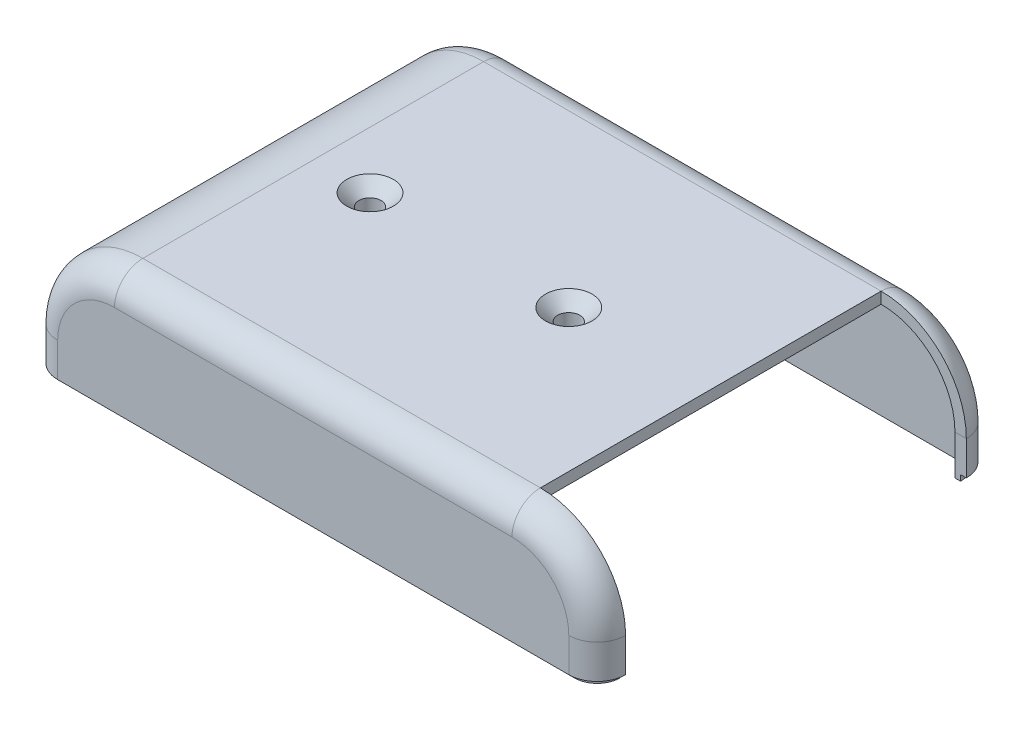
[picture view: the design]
ISO-10303-21;
HEADER;
FILE_DESCRIPTION(('STEP AP214'),'2;1');
FILE_NAME('part.step','',(''),(''),'','','');
FILE_SCHEMA(('AUTOMOTIVE_DESIGN { 1 0 10303 214 1 1 1 1 }'));
ENDSEC;
DATA;
#1=APPLICATION_CONTEXT('core data for automotive mechanical design processes');
#2=APPLICATION_PROTOCOL_DEFINITION('international standard','automotive_design',2000,#1);
#3=PRODUCT_CONTEXT('',#1,'mechanical');
#4=PRODUCT('Part','Part','',(#3));
#5=PRODUCT_RELATED_PRODUCT_CATEGORY('part','',(#4));
#6=PRODUCT_DEFINITION_FORMATION('','',#4);
#7=PRODUCT_DEFINITION_CONTEXT('part definition',#1,'design');
#8=PRODUCT_DEFINITION('design','',#6,#7);
#9=PRODUCT_DEFINITION_SHAPE('','',#8);
#10=(LENGTH_UNIT() NAMED_UNIT(*) SI_UNIT(.MILLI.,.METRE.));
#11=(NAMED_UNIT(*) PLANE_ANGLE_UNIT() SI_UNIT($,.RADIAN.));
#12=(NAMED_UNIT(*) SI_UNIT($,.STERADIAN.) SOLID_ANGLE_UNIT());
#13=UNCERTAINTY_MEASURE_WITH_UNIT(LENGTH_MEASURE(1.E-05),#10,'distance_accuracy_value','');
#14=(GEOMETRIC_REPRESENTATION_CONTEXT(3) GLOBAL_UNCERTAINTY_ASSIGNED_CONTEXT((#13)) GLOBAL_UNIT_ASSIGNED_CONTEXT((#10,
#11,#12)) REPRESENTATION_CONTEXT('',''));
#15=CARTESIAN_POINT('',(0.,0.,0.));
#16=DIRECTION('',(0.,0.,1.));
#17=DIRECTION('',(1.,0.,0.));
#18=AXIS2_PLACEMENT_3D('',#15,#16,#17);
#19=CARTESIAN_POINT('',(-50.,21.,-35.));
#20=DIRECTION('',(0.,0.,1.));
#21=DIRECTION('',(1.,0.,0.));
#22=AXIS2_PLACEMENT_3D('',#19,#20,#21);
#23=PLANE('',#22);
#24=CARTESIAN_POINT('',(35.,6.,-35.));
#25=DIRECTION('',(0.,0.,1.));
#26=DIRECTION('',(1.,0.,0.));
#27=AXIS2_PLACEMENT_3D('',#24,#25,#26);
#28=CIRCLE('',#27,10.);
#29=CARTESIAN_POINT('',(35.,16.,-35.));
#30=VERTEX_POINT('',#29);
#31=CARTESIAN_POINT('',(45.,6.,-35.));
#32=VERTEX_POINT('',#31);
#33=EDGE_CURVE('E472',#30,#32,#28,.F.);
#34=ORIENTED_EDGE('',*,*,#33,.T.);
#35=DIRECTION('',(0.,-1.,0.));
#36=VECTOR('',#35,1.);
#37=CARTESIAN_POINT('',(45.,21.,-35.));
#38=LINE('',#37,#36);
#39=CARTESIAN_POINT('',(45.,0.,-35.));
#40=VERTEX_POINT('',#39);
#41=EDGE_CURVE('E474',#32,#40,#38,.T.);
#42=ORIENTED_EDGE('',*,*,#41,.T.);
#43=DIRECTION('',(-1.,0.,0.));
#44=VECTOR('',#43,1.);
#45=CARTESIAN_POINT('',(-50.,0.,-35.));
#46=LINE('',#45,#44);
#47=CARTESIAN_POINT('',(-45.,0.,-35.));
#48=VERTEX_POINT('',#47);
#49=EDGE_CURVE('E447',#40,#48,#46,.T.);
#50=ORIENTED_EDGE('',*,*,#49,.T.);
#51=DIRECTION('',(0.,-1.,0.));
#52=VECTOR('',#51,1.);
#53=CARTESIAN_POINT('',(-45.,21.,-35.));
#54=LINE('',#53,#52);
#55=CARTESIAN_POINT('',(-45.,6.,-35.));
#56=VERTEX_POINT('',#55);
#57=EDGE_CURVE('E470',#48,#56,#54,.F.);
#58=ORIENTED_EDGE('',*,*,#57,.T.);
#59=CARTESIAN_POINT('',(-35.,6.,-35.));
#60=DIRECTION('',(0.,0.,1.));
#61=DIRECTION('',(1.,0.,0.));
#62=AXIS2_PLACEMENT_3D('',#59,#60,#61);
#63=CIRCLE('',#62,10.);
#64=CARTESIAN_POINT('',(-35.,16.,-35.));
#65=VERTEX_POINT('',#64);
#66=EDGE_CURVE('E468',#56,#65,#63,.F.);
#67=ORIENTED_EDGE('',*,*,#66,.T.);
#68=DIRECTION('',(-1.,0.,0.));
#69=VECTOR('',#68,1.);
#70=CARTESIAN_POINT('',(-50.,16.,-35.));
#71=LINE('',#70,#69);
#72=EDGE_CURVE('E466',#65,#30,#71,.F.);
#73=ORIENTED_EDGE('',*,*,#72,.T.);
#74=EDGE_LOOP('',(#34,#42,#50,#58,#67,#73));
#75=FACE_BOUND('',#74,.T.);
#76=ADVANCED_FACE('F36',(#75),#23,.F.);
#77=CARTESIAN_POINT('',(-50.,21.,35.));
#78=DIRECTION('',(1.,0.,0.));
#79=DIRECTION('',(0.,0.,-1.));
#80=AXIS2_PLACEMENT_3D('',#77,#78,#79);
#81=PLANE('',#80);
#82=DIRECTION('',(0.,0.,1.));
#83=VECTOR('',#82,1.);
#84=CARTESIAN_POINT('',(-50.,6.,35.));
#85=LINE('',#84,#83);
#86=CARTESIAN_POINT('',(-50.,6.,30.));
#87=VERTEX_POINT('',#86);
#88=CARTESIAN_POINT('',(-50.,6.,-30.));
#89=VERTEX_POINT('',#88);
#90=EDGE_CURVE('E463',#87,#89,#85,.F.);
#91=ORIENTED_EDGE('',*,*,#90,.T.);
#92=DIRECTION('',(0.,-1.,0.));
#93=VECTOR('',#92,1.);
#94=CARTESIAN_POINT('',(-50.,21.,-30.));
#95=LINE('',#94,#93);
#96=CARTESIAN_POINT('',(-50.,0.,-30.));
#97=VERTEX_POINT('',#96);
#98=EDGE_CURVE('E497',#89,#97,#95,.T.);
#99=ORIENTED_EDGE('',*,*,#98,.T.);
#100=DIRECTION('',(0.,0.,1.));
#101=VECTOR('',#100,1.);
#102=CARTESIAN_POINT('',(-50.,0.,35.));
#103=LINE('',#102,#101);
#104=CARTESIAN_POINT('',(-50.,0.,30.));
#105=VERTEX_POINT('',#104);
#106=EDGE_CURVE('E450',#97,#105,#103,.T.);
#107=ORIENTED_EDGE('',*,*,#106,.T.);
#108=DIRECTION('',(0.,-1.,0.));
#109=VECTOR('',#108,1.);
#110=CARTESIAN_POINT('',(-50.,21.,30.));
#111=LINE('',#110,#109);
#112=EDGE_CURVE('E495',#105,#87,#111,.F.);
#113=ORIENTED_EDGE('',*,*,#112,.T.);
#114=EDGE_LOOP('',(#91,#99,#107,#113));
#115=FACE_BOUND('',#114,.T.);
#116=ADVANCED_FACE('F582',(#115),#81,.F.);
#117=CARTESIAN_POINT('',(-50.,21.,35.));
#118=DIRECTION('',(0.,0.,-1.));
#119=DIRECTION('',(-1.,0.,0.));
#120=AXIS2_PLACEMENT_3D('',#117,#118,#119);
#121=PLANE('',#120);
#122=CARTESIAN_POINT('',(-35.,6.,35.));
#123=DIRECTION('',(0.,0.,-1.));
#124=DIRECTION('',(-1.,0.,0.));
#125=AXIS2_PLACEMENT_3D('',#122,#123,#124);
#126=CIRCLE('',#125,10.);
#127=CARTESIAN_POINT('',(-35.,16.,35.));
#128=VERTEX_POINT('',#127);
#129=CARTESIAN_POINT('',(-45.,6.,35.));
#130=VERTEX_POINT('',#129);
#131=EDGE_CURVE('E509',#128,#130,#126,.F.);
#132=ORIENTED_EDGE('',*,*,#131,.T.);
#133=DIRECTION('',(0.,-1.,0.));
#134=VECTOR('',#133,1.);
#135=CARTESIAN_POINT('',(-45.,21.,35.));
#136=LINE('',#135,#134);
#137=CARTESIAN_POINT('',(-45.,0.,35.));
#138=VERTEX_POINT('',#137);
#139=EDGE_CURVE('E511',#130,#138,#136,.T.);
#140=ORIENTED_EDGE('',*,*,#139,.T.);
#141=DIRECTION('',(1.,0.,0.));
#142=VECTOR('',#141,1.);
#143=CARTESIAN_POINT('',(-50.,0.,35.));
#144=LINE('',#143,#142);
#145=CARTESIAN_POINT('',(45.,0.,35.));
#146=VERTEX_POINT('',#145);
#147=EDGE_CURVE('E454',#138,#146,#144,.T.);
#148=ORIENTED_EDGE('',*,*,#147,.T.);
#149=DIRECTION('',(0.,-1.,0.));
#150=VECTOR('',#149,1.);
#151=CARTESIAN_POINT('',(45.,21.,35.));
#152=LINE('',#151,#150);
#153=CARTESIAN_POINT('',(45.,6.,35.));
#154=VERTEX_POINT('',#153);
#155=EDGE_CURVE('E507',#146,#154,#152,.F.);
#156=ORIENTED_EDGE('',*,*,#155,.T.);
#157=CARTESIAN_POINT('',(35.,6.,35.));
#158=DIRECTION('',(0.,0.,-1.));
#159=DIRECTION('',(-1.,0.,0.));
#160=AXIS2_PLACEMENT_3D('',#157,#158,#159);
#161=CIRCLE('',#160,10.);
#162=CARTESIAN_POINT('',(35.,16.,35.));
#163=VERTEX_POINT('',#162);
#164=EDGE_CURVE('E505',#154,#163,#161,.F.);
#165=ORIENTED_EDGE('',*,*,#164,.T.);
#166=DIRECTION('',(1.,0.,0.));
#167=VECTOR('',#166,1.);
#168=CARTESIAN_POINT('',(-50.,16.,35.));
#169=LINE('',#168,#167);
#170=EDGE_CURVE('E503',#163,#128,#169,.F.);
#171=ORIENTED_EDGE('',*,*,#170,.T.);
#172=EDGE_LOOP('',(#132,#140,#148,#156,#165,#171));
#173=FACE_BOUND('',#172,.T.);
#174=ADVANCED_FACE('F588',(#173),#121,.F.);
#175=CARTESIAN_POINT('',(0.,21.,0.));
#176=DIRECTION('',(0.,-1.,0.));
#177=DIRECTION('',(0.,0.,-1.));
#178=AXIS2_PLACEMENT_3D('',#175,#176,#177);
#179=PLANE('',#178);
#180=CARTESIAN_POINT('',(-25.,21.,0.));
#181=DIRECTION('',(0.,1.,0.));
#182=DIRECTION('',(0.,0.,1.));
#183=AXIS2_PLACEMENT_3D('',#180,#181,#182);
#184=CIRCLE('',#183,4.1);
#185=CARTESIAN_POINT('',(-25.,21.,4.1));
#186=VERTEX_POINT('',#185);
#187=EDGE_CURVE('E260',#186,#186,#184,.T.);
#188=ORIENTED_EDGE('',*,*,#187,.F.);
#189=EDGE_LOOP('',(#188));
#190=FACE_BOUND('',#189,.T.);
#191=CARTESIAN_POINT('',(9.99999999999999,21.,0.));
#192=DIRECTION('',(0.,1.,0.));
#193=DIRECTION('',(0.,0.,1.));
#194=AXIS2_PLACEMENT_3D('',#191,#192,#193);
#195=CIRCLE('',#194,4.1);
#196=CARTESIAN_POINT('',(9.99999999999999,21.,4.1));
#197=VERTEX_POINT('',#196);
#198=EDGE_CURVE('E343',#197,#197,#195,.T.);
#199=ORIENTED_EDGE('',*,*,#198,.F.);
#200=EDGE_LOOP('',(#199));
#201=FACE_BOUND('',#200,.T.);
#202=DIRECTION('',(0.,0.,-1.));
#203=VECTOR('',#202,1.);
#204=CARTESIAN_POINT('',(35.,21.,0.));
#205=LINE('',#204,#203);
#206=CARTESIAN_POINT('',(35.,21.,30.));
#207=VERTEX_POINT('',#206);
#208=CARTESIAN_POINT('',(35.,21.,-30.));
#209=VERTEX_POINT('',#208);
#210=EDGE_CURVE('E460',#207,#209,#205,.T.);
#211=ORIENTED_EDGE('',*,*,#210,.T.);
#212=DIRECTION('',(-1.,0.,0.));
#213=VECTOR('',#212,1.);
#214=CARTESIAN_POINT('',(0.,21.,-30.));
#215=LINE('',#214,#213);
#216=CARTESIAN_POINT('',(-35.,21.,-30.));
#217=VERTEX_POINT('',#216);
#218=EDGE_CURVE('E517',#209,#217,#215,.T.);
#219=ORIENTED_EDGE('',*,*,#218,.T.);
#220=DIRECTION('',(0.,0.,1.));
#221=VECTOR('',#220,1.);
#222=CARTESIAN_POINT('',(-35.,21.,0.));
#223=LINE('',#222,#221);
#224=CARTESIAN_POINT('',(-35.,21.,30.));
#225=VERTEX_POINT('',#224);
#226=EDGE_CURVE('E457',#217,#225,#223,.T.);
#227=ORIENTED_EDGE('',*,*,#226,.T.);
#228=DIRECTION('',(1.,0.,0.));
#229=VECTOR('',#228,1.);
#230=CARTESIAN_POINT('',(0.,21.,30.));
#231=LINE('',#230,#229);
#232=EDGE_CURVE('E514',#225,#207,#231,.T.);
#233=ORIENTED_EDGE('',*,*,#232,.T.);
#234=EDGE_LOOP('',(#211,#219,#227,#233));
#235=FACE_BOUND('',#234,.T.);
#236=ADVANCED_FACE('F674',(#190,#201,#235),#179,.F.);
#237=CARTESIAN_POINT('',(0.,0.,0.));
#238=DIRECTION('',(0.,-1.,0.));
#239=DIRECTION('',(0.,0.,-1.));
#240=AXIS2_PLACEMENT_3D('',#237,#238,#239);
#241=PLANE('',#240);
#242=CARTESIAN_POINT('',(45.,0.,-30.));
#243=DIRECTION('',(0.,-1.,0.));
#244=DIRECTION('',(1.,0.,0.));
#245=AXIS2_PLACEMENT_3D('',#242,#243,#244);
#246=CIRCLE('',#245,4.);
#247=CARTESIAN_POINT('',(45.,0.,-34.));
#248=VERTEX_POINT('',#247);
#249=CARTESIAN_POINT('',(49.,0.,-30.));
#250=VERTEX_POINT('',#249);
#251=EDGE_CURVE('E51',#248,#250,#246,.T.);
#252=ORIENTED_EDGE('',*,*,#251,.F.);
#253=DIRECTION('',(1.,0.,0.));
#254=VECTOR('',#253,1.);
#255=CARTESIAN_POINT('',(45.,0.,-34.));
#256=LINE('',#255,#254);
#257=CARTESIAN_POINT('',(-45.,0.,-34.));
#258=VERTEX_POINT('',#257);
#259=EDGE_CURVE('E55',#258,#248,#256,.T.);
#260=ORIENTED_EDGE('',*,*,#259,.F.);
#261=CARTESIAN_POINT('',(-45.,0.,-30.));
#262=DIRECTION('',(0.,-1.,0.));
#263=DIRECTION('',(1.,0.,0.));
#264=AXIS2_PLACEMENT_3D('',#261,#262,#263);
#265=CIRCLE('',#264,4.00000000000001);
#266=CARTESIAN_POINT('',(-49.,0.,-30.));
#267=VERTEX_POINT('',#266);
#268=EDGE_CURVE('E316',#267,#258,#265,.T.);
#269=ORIENTED_EDGE('',*,*,#268,.F.);
#270=DIRECTION('',(0.,0.,1.));
#271=VECTOR('',#270,1.);
#272=CARTESIAN_POINT('',(-49.,0.,-30.));
#273=LINE('',#272,#271);
#274=CARTESIAN_POINT('',(-49.,0.,30.));
#275=VERTEX_POINT('',#274);
#276=EDGE_CURVE('E313',#275,#267,#273,.F.);
#277=ORIENTED_EDGE('',*,*,#276,.F.);
#278=CARTESIAN_POINT('',(-45.,0.,30.));
#279=DIRECTION('',(0.,-1.,0.));
#280=DIRECTION('',(1.,0.,0.));
#281=AXIS2_PLACEMENT_3D('',#278,#279,#280);
#282=CIRCLE('',#281,4.);
#283=CARTESIAN_POINT('',(-45.,0.,34.));
#284=VERTEX_POINT('',#283);
#285=EDGE_CURVE('E310',#284,#275,#282,.T.);
#286=ORIENTED_EDGE('',*,*,#285,.F.);
#287=DIRECTION('',(-1.,0.,0.));
#288=VECTOR('',#287,1.);
#289=CARTESIAN_POINT('',(-45.,0.,34.));
#290=LINE('',#289,#288);
#291=CARTESIAN_POINT('',(45.,0.,34.));
#292=VERTEX_POINT('',#291);
#293=EDGE_CURVE('E307',#292,#284,#290,.T.);
#294=ORIENTED_EDGE('',*,*,#293,.F.);
#295=CARTESIAN_POINT('',(45.,0.,30.));
#296=DIRECTION('',(0.,-1.,0.));
#297=DIRECTION('',(1.,0.,0.));
#298=AXIS2_PLACEMENT_3D('',#295,#296,#297);
#299=CIRCLE('',#298,4.);
#300=CARTESIAN_POINT('',(49.,0.,30.));
#301=VERTEX_POINT('',#300);
#302=EDGE_CURVE('E304',#301,#292,#299,.T.);
#303=ORIENTED_EDGE('',*,*,#302,.F.);
#304=DIRECTION('',(-1.,0.,0.));
#305=VECTOR('',#304,1.);
#306=CARTESIAN_POINT('',(50.,0.,30.));
#307=LINE('',#306,#305);
#308=CARTESIAN_POINT('',(50.,0.,30.));
#309=VERTEX_POINT('',#308);
#310=EDGE_CURVE('E357',#301,#309,#307,.F.);
#311=ORIENTED_EDGE('',*,*,#310,.T.);
#312=CARTESIAN_POINT('',(45.,0.,30.));
#313=DIRECTION('',(0.,-1.,0.));
#314=DIRECTION('',(0.,0.,-1.));
#315=AXIS2_PLACEMENT_3D('',#312,#313,#314);
#316=CIRCLE('',#315,5.);
#317=EDGE_CURVE('E477',#309,#146,#316,.T.);
#318=ORIENTED_EDGE('',*,*,#317,.T.);
#319=ORIENTED_EDGE('',*,*,#147,.F.);
#320=CARTESIAN_POINT('',(-45.,0.,30.));
#321=DIRECTION('',(0.,-1.,0.));
#322=DIRECTION('',(0.,0.,-1.));
#323=AXIS2_PLACEMENT_3D('',#320,#321,#322);
#324=CIRCLE('',#323,5.);
#325=EDGE_CURVE('E479',#138,#105,#324,.T.);
#326=ORIENTED_EDGE('',*,*,#325,.T.);
#327=ORIENTED_EDGE('',*,*,#106,.F.);
#328=CARTESIAN_POINT('',(-45.,0.,-30.));
#329=DIRECTION('',(0.,-1.,0.));
#330=DIRECTION('',(0.,0.,-1.));
#331=AXIS2_PLACEMENT_3D('',#328,#329,#330);
#332=CIRCLE('',#331,5.);
#333=EDGE_CURVE('E481',#97,#48,#332,.T.);
#334=ORIENTED_EDGE('',*,*,#333,.T.);
#335=ORIENTED_EDGE('',*,*,#49,.F.);
#336=CARTESIAN_POINT('',(45.,0.,-30.));
#337=DIRECTION('',(0.,-1.,0.));
#338=DIRECTION('',(0.,0.,-1.));
#339=AXIS2_PLACEMENT_3D('',#336,#337,#338);
#340=CIRCLE('',#339,5.);
#341=CARTESIAN_POINT('',(50.,0.,-30.));
#342=VERTEX_POINT('',#341);
#343=EDGE_CURVE('E483',#40,#342,#340,.T.);
#344=ORIENTED_EDGE('',*,*,#343,.T.);
#345=DIRECTION('',(-1.,0.,0.));
#346=VECTOR('',#345,1.);
#347=CARTESIAN_POINT('',(50.,0.,-30.));
#348=LINE('',#347,#346);
#349=EDGE_CURVE('E360',#250,#342,#348,.F.);
#350=ORIENTED_EDGE('',*,*,#349,.F.);
#351=EDGE_LOOP('',(#252,#260,#269,#277,#286,#294,#303,#311,#318,#319,#326,#327,#334,#335,#344,#350));
#352=FACE_BOUND('',#351,.T.);
#353=ADVANCED_FACE('F597',(#352),#241,.T.);
#354=CARTESIAN_POINT('',(-35.,6.,0.));
#355=DIRECTION('',(0.,0.,1.));
#356=DIRECTION('',(1.,0.,0.));
#357=AXIS2_PLACEMENT_3D('',#354,#355,#356);
#358=CYLINDRICAL_SURFACE('',#357,15.);
#359=ORIENTED_EDGE('',*,*,#226,.F.);
#360=CARTESIAN_POINT('',(-35.,6.,-30.));
#361=DIRECTION('',(0.,0.,1.));
#362=DIRECTION('',(1.,0.,0.));
#363=AXIS2_PLACEMENT_3D('',#360,#361,#362);
#364=CIRCLE('',#363,15.);
#365=EDGE_CURVE('E501',#217,#89,#364,.T.);
#366=ORIENTED_EDGE('',*,*,#365,.T.);
#367=ORIENTED_EDGE('',*,*,#90,.F.);
#368=CARTESIAN_POINT('',(-35.,6.,30.));
#369=DIRECTION('',(0.,0.,-1.));
#370=DIRECTION('',(-1.,0.,0.));
#371=AXIS2_PLACEMENT_3D('',#368,#369,#370);
#372=CIRCLE('',#371,15.);
#373=EDGE_CURVE('E499',#87,#225,#372,.T.);
#374=ORIENTED_EDGE('',*,*,#373,.T.);
#375=EDGE_LOOP('',(#359,#366,#367,#374));
#376=FACE_BOUND('',#375,.T.);
#377=ADVANCED_FACE('F593',(#376),#358,.T.);
#378=CARTESIAN_POINT('',(-45.,21.,-30.));
#379=DIRECTION('',(0.,-1.,0.));
#380=DIRECTION('',(0.,0.,-1.));
#381=AXIS2_PLACEMENT_3D('',#378,#379,#380);
#382=CYLINDRICAL_SURFACE('',#381,5.);
#383=ORIENTED_EDGE('',*,*,#333,.F.);
#384=ORIENTED_EDGE('',*,*,#98,.F.);
#385=CARTESIAN_POINT('',(-45.,6.,-30.));
#386=DIRECTION('',(0.,1.,0.));
#387=DIRECTION('',(0.,0.,1.));
#388=AXIS2_PLACEMENT_3D('',#385,#386,#387);
#389=CIRCLE('',#388,5.);
#390=EDGE_CURVE('E451',#56,#89,#389,.T.);
#391=ORIENTED_EDGE('',*,*,#390,.F.);
#392=ORIENTED_EDGE('',*,*,#57,.F.);
#393=EDGE_LOOP('',(#383,#384,#391,#392));
#394=FACE_BOUND('',#393,.T.);
#395=ADVANCED_FACE('F596',(#394),#382,.T.);
#396=CARTESIAN_POINT('',(-35.,6.,-30.));
#397=DIRECTION('',(0.,0.,1.));
#398=DIRECTION('',(1.,0.,0.));
#399=AXIS2_PLACEMENT_3D('',#396,#397,#398);
#400=TOROIDAL_SURFACE('',#399,10.,5.);
#401=ORIENTED_EDGE('',*,*,#390,.T.);
#402=ORIENTED_EDGE('',*,*,#365,.F.);
#403=CARTESIAN_POINT('',(-35.,16.,-30.));
#404=DIRECTION('',(1.,0.,0.));
#405=DIRECTION('',(0.,0.,-1.));
#406=AXIS2_PLACEMENT_3D('',#403,#404,#405);
#407=CIRCLE('',#406,5.);
#408=EDGE_CURVE('E527',#65,#217,#407,.T.);
#409=ORIENTED_EDGE('',*,*,#408,.F.);
#410=ORIENTED_EDGE('',*,*,#66,.F.);
#411=EDGE_LOOP('',(#401,#402,#409,#410));
#412=FACE_BOUND('',#411,.T.);
#413=ADVANCED_FACE('F611',(#412),#400,.T.);
#414=CARTESIAN_POINT('',(0.,16.,-30.));
#415=DIRECTION('',(-1.,0.,0.));
#416=DIRECTION('',(0.,0.,1.));
#417=AXIS2_PLACEMENT_3D('',#414,#415,#416);
#418=CYLINDRICAL_SURFACE('',#417,5.);
#419=ORIENTED_EDGE('',*,*,#408,.T.);
#420=ORIENTED_EDGE('',*,*,#218,.F.);
#421=CARTESIAN_POINT('',(35.,16.,-30.));
#422=DIRECTION('',(1.,0.,0.));
#423=DIRECTION('',(0.,0.,-1.));
#424=AXIS2_PLACEMENT_3D('',#421,#422,#423);
#425=CIRCLE('',#424,5.);
#426=EDGE_CURVE('E523',#30,#209,#425,.T.);
#427=ORIENTED_EDGE('',*,*,#426,.F.);
#428=ORIENTED_EDGE('',*,*,#72,.F.);
#429=EDGE_LOOP('',(#419,#420,#427,#428));
#430=FACE_BOUND('',#429,.T.);
#431=ADVANCED_FACE('F607',(#430),#418,.T.);
#432=CARTESIAN_POINT('',(35.,6.,-30.));
#433=DIRECTION('',(0.,0.,1.));
#434=DIRECTION('',(1.,0.,0.));
#435=AXIS2_PLACEMENT_3D('',#432,#433,#434);
#436=TOROIDAL_SURFACE('',#435,10.,5.);
#437=ORIENTED_EDGE('',*,*,#426,.T.);
#438=CARTESIAN_POINT('',(35.,6.,-30.));
#439=DIRECTION('',(0.,0.,1.));
#440=DIRECTION('',(1.,0.,0.));
#441=AXIS2_PLACEMENT_3D('',#438,#439,#440);
#442=CIRCLE('',#441,15.);
#443=CARTESIAN_POINT('',(50.,6.,-30.));
#444=VERTEX_POINT('',#443);
#445=EDGE_CURVE('E493',#444,#209,#442,.T.);
#446=ORIENTED_EDGE('',*,*,#445,.F.);
#447=CARTESIAN_POINT('',(45.,6.,-30.));
#448=DIRECTION('',(0.,-1.,0.));
#449=DIRECTION('',(0.,0.,-1.));
#450=AXIS2_PLACEMENT_3D('',#447,#448,#449);
#451=CIRCLE('',#450,5.);
#452=EDGE_CURVE('E520',#32,#444,#451,.T.);
#453=ORIENTED_EDGE('',*,*,#452,.F.);
#454=ORIENTED_EDGE('',*,*,#33,.F.);
#455=EDGE_LOOP('',(#437,#446,#453,#454));
#456=FACE_BOUND('',#455,.T.);
#457=ADVANCED_FACE('F603',(#456),#436,.T.);
#458=CARTESIAN_POINT('',(45.,21.,-30.));
#459=DIRECTION('',(0.,-1.,0.));
#460=DIRECTION('',(0.,0.,-1.));
#461=AXIS2_PLACEMENT_3D('',#458,#459,#460);
#462=CYLINDRICAL_SURFACE('',#461,5.);
#463=ORIENTED_EDGE('',*,*,#452,.T.);
#464=DIRECTION('',(0.,-1.,0.));
#465=VECTOR('',#464,1.);
#466=CARTESIAN_POINT('',(50.,21.,-30.));
#467=LINE('',#466,#465);
#468=EDGE_CURVE('E489',#342,#444,#467,.F.);
#469=ORIENTED_EDGE('',*,*,#468,.F.);
#470=ORIENTED_EDGE('',*,*,#343,.F.);
#471=ORIENTED_EDGE('',*,*,#41,.F.);
#472=EDGE_LOOP('',(#463,#469,#470,#471));
#473=FACE_BOUND('',#472,.T.);
#474=ADVANCED_FACE('F599',(#473),#462,.T.);
#475=CARTESIAN_POINT('',(45.,21.,30.));
#476=DIRECTION('',(0.,-1.,0.));
#477=DIRECTION('',(0.,0.,-1.));
#478=AXIS2_PLACEMENT_3D('',#475,#476,#477);
#479=CYLINDRICAL_SURFACE('',#478,5.);
#480=ORIENTED_EDGE('',*,*,#317,.F.);
#481=DIRECTION('',(0.,-1.,0.));
#482=VECTOR('',#481,1.);
#483=CARTESIAN_POINT('',(50.,21.,30.));
#484=LINE('',#483,#482);
#485=CARTESIAN_POINT('',(50.,6.,30.));
#486=VERTEX_POINT('',#485);
#487=EDGE_CURVE('E486',#486,#309,#484,.T.);
#488=ORIENTED_EDGE('',*,*,#487,.F.);
#489=CARTESIAN_POINT('',(45.,6.,30.));
#490=DIRECTION('',(0.,1.,0.));
#491=DIRECTION('',(0.,0.,1.));
#492=AXIS2_PLACEMENT_3D('',#489,#490,#491);
#493=CIRCLE('',#492,5.);
#494=EDGE_CURVE('E524',#154,#486,#493,.T.);
#495=ORIENTED_EDGE('',*,*,#494,.F.);
#496=ORIENTED_EDGE('',*,*,#155,.F.);
#497=EDGE_LOOP('',(#480,#488,#495,#496));
#498=FACE_BOUND('',#497,.T.);
#499=ADVANCED_FACE('F602',(#498),#479,.T.);
#500=CARTESIAN_POINT('',(35.,6.,30.));
#501=DIRECTION('',(0.,0.,-1.));
#502=DIRECTION('',(-1.,0.,0.));
#503=AXIS2_PLACEMENT_3D('',#500,#501,#502);
#504=TOROIDAL_SURFACE('',#503,10.,5.);
#505=ORIENTED_EDGE('',*,*,#494,.T.);
#506=CARTESIAN_POINT('',(35.,6.,30.));
#507=DIRECTION('',(0.,0.,-1.));
#508=DIRECTION('',(-1.,0.,0.));
#509=AXIS2_PLACEMENT_3D('',#506,#507,#508);
#510=CIRCLE('',#509,15.);
#511=EDGE_CURVE('E491',#207,#486,#510,.T.);
#512=ORIENTED_EDGE('',*,*,#511,.F.);
#513=CARTESIAN_POINT('',(35.,16.,30.));
#514=DIRECTION('',(-1.,0.,0.));
#515=DIRECTION('',(0.,0.,1.));
#516=AXIS2_PLACEMENT_3D('',#513,#514,#515);
#517=CIRCLE('',#516,5.);
#518=EDGE_CURVE('E537',#163,#207,#517,.T.);
#519=ORIENTED_EDGE('',*,*,#518,.F.);
#520=ORIENTED_EDGE('',*,*,#164,.F.);
#521=EDGE_LOOP('',(#505,#512,#519,#520));
#522=FACE_BOUND('',#521,.T.);
#523=ADVANCED_FACE('F631',(#522),#504,.T.);
#524=CARTESIAN_POINT('',(0.,16.,30.));
#525=DIRECTION('',(1.,0.,0.));
#526=DIRECTION('',(0.,0.,-1.));
#527=AXIS2_PLACEMENT_3D('',#524,#525,#526);
#528=CYLINDRICAL_SURFACE('',#527,5.);
#529=ORIENTED_EDGE('',*,*,#518,.T.);
#530=ORIENTED_EDGE('',*,*,#232,.F.);
#531=CARTESIAN_POINT('',(-35.,16.,30.));
#532=DIRECTION('',(-1.,0.,0.));
#533=DIRECTION('',(0.,0.,1.));
#534=AXIS2_PLACEMENT_3D('',#531,#532,#533);
#535=CIRCLE('',#534,5.);
#536=EDGE_CURVE('E534',#128,#225,#535,.T.);
#537=ORIENTED_EDGE('',*,*,#536,.F.);
#538=ORIENTED_EDGE('',*,*,#170,.F.);
#539=EDGE_LOOP('',(#529,#530,#537,#538));
#540=FACE_BOUND('',#539,.T.);
#541=ADVANCED_FACE('F627',(#540),#528,.T.);
#542=CARTESIAN_POINT('',(-35.,6.,30.));
#543=DIRECTION('',(0.,0.,-1.));
#544=DIRECTION('',(-1.,0.,0.));
#545=AXIS2_PLACEMENT_3D('',#542,#543,#544);
#546=TOROIDAL_SURFACE('',#545,10.,5.);
#547=ORIENTED_EDGE('',*,*,#536,.T.);
#548=ORIENTED_EDGE('',*,*,#373,.F.);
#549=CARTESIAN_POINT('',(-45.,6.,30.));
#550=DIRECTION('',(0.,-1.,0.));
#551=DIRECTION('',(0.,0.,-1.));
#552=AXIS2_PLACEMENT_3D('',#549,#550,#551);
#553=CIRCLE('',#552,5.);
#554=EDGE_CURVE('E446',#130,#87,#553,.T.);
#555=ORIENTED_EDGE('',*,*,#554,.F.);
#556=ORIENTED_EDGE('',*,*,#131,.F.);
#557=EDGE_LOOP('',(#547,#548,#555,#556));
#558=FACE_BOUND('',#557,.T.);
#559=ADVANCED_FACE('F623',(#558),#546,.T.);
#560=CARTESIAN_POINT('',(-45.,21.,30.));
#561=DIRECTION('',(0.,-1.,0.));
#562=DIRECTION('',(0.,0.,-1.));
#563=AXIS2_PLACEMENT_3D('',#560,#561,#562);
#564=CYLINDRICAL_SURFACE('',#563,5.);
#565=ORIENTED_EDGE('',*,*,#554,.T.);
#566=ORIENTED_EDGE('',*,*,#112,.F.);
#567=ORIENTED_EDGE('',*,*,#325,.F.);
#568=ORIENTED_EDGE('',*,*,#139,.F.);
#569=EDGE_LOOP('',(#565,#566,#567,#568));
#570=FACE_BOUND('',#569,.T.);
#571=ADVANCED_FACE('F619',(#570),#564,.T.);
#572=CARTESIAN_POINT('',(35.,6.,30.));
#573=DIRECTION('',(0.,0.,1.));
#574=DIRECTION('',(1.,0.,0.));
#575=AXIS2_PLACEMENT_3D('',#572,#573,#574);
#576=PLANE('',#575);
#577=ORIENTED_EDGE('',*,*,#511,.T.);
#578=DIRECTION('',(1.,0.,0.));
#579=VECTOR('',#578,1.);
#580=CARTESIAN_POINT('',(50.,6.,30.));
#581=LINE('',#580,#579);
#582=CARTESIAN_POINT('',(48.,6.,30.));
#583=VERTEX_POINT('',#582);
#584=EDGE_CURVE('E359',#583,#486,#581,.T.);
#585=ORIENTED_EDGE('',*,*,#584,.F.);
#586=CARTESIAN_POINT('',(35.,6.,30.));
#587=DIRECTION('',(0.,0.,1.));
#588=DIRECTION('',(1.,0.,0.));
#589=AXIS2_PLACEMENT_3D('',#586,#587,#588);
#590=CIRCLE('',#589,13.);
#591=CARTESIAN_POINT('',(35.,19.,30.));
#592=VERTEX_POINT('',#591);
#593=EDGE_CURVE('E434',#592,#583,#590,.F.);
#594=ORIENTED_EDGE('',*,*,#593,.F.);
#595=DIRECTION('',(0.,1.,0.));
#596=VECTOR('',#595,1.);
#597=CARTESIAN_POINT('',(35.,6.,30.));
#598=LINE('',#597,#596);
#599=EDGE_CURVE('E444',#592,#207,#598,.T.);
#600=ORIENTED_EDGE('',*,*,#599,.T.);
#601=EDGE_LOOP('',(#577,#585,#594,#600));
#602=FACE_BOUND('',#601,.T.);
#603=ADVANCED_FACE('F622',(#602),#576,.F.);
#604=CARTESIAN_POINT('',(35.,21.,0.));
#605=DIRECTION('',(1.,0.,0.));
#606=DIRECTION('',(0.,0.,-1.));
#607=AXIS2_PLACEMENT_3D('',#604,#605,#606);
#608=PLANE('',#607);
#609=ORIENTED_EDGE('',*,*,#210,.F.);
#610=ORIENTED_EDGE('',*,*,#599,.F.);
#611=DIRECTION('',(0.,0.,1.));
#612=VECTOR('',#611,1.);
#613=CARTESIAN_POINT('',(35.,19.,0.));
#614=LINE('',#613,#612);
#615=CARTESIAN_POINT('',(35.,19.,-30.));
#616=VERTEX_POINT('',#615);
#617=EDGE_CURVE('E431',#592,#616,#614,.F.);
#618=ORIENTED_EDGE('',*,*,#617,.T.);
#619=DIRECTION('',(0.,1.,0.));
#620=VECTOR('',#619,1.);
#621=CARTESIAN_POINT('',(35.,21.,-30.));
#622=LINE('',#621,#620);
#623=EDGE_CURVE('E441',#616,#209,#622,.T.);
#624=ORIENTED_EDGE('',*,*,#623,.T.);
#625=EDGE_LOOP('',(#609,#610,#618,#624));
#626=FACE_BOUND('',#625,.T.);
#627=ADVANCED_FACE('F718',(#626),#608,.T.);
#628=CARTESIAN_POINT('',(35.,6.,-30.));
#629=DIRECTION('',(0.,0.,-1.));
#630=DIRECTION('',(-1.,0.,0.));
#631=AXIS2_PLACEMENT_3D('',#628,#629,#630);
#632=PLANE('',#631);
#633=ORIENTED_EDGE('',*,*,#445,.T.);
#634=ORIENTED_EDGE('',*,*,#623,.F.);
#635=CARTESIAN_POINT('',(35.,6.,-30.));
#636=DIRECTION('',(0.,0.,-1.));
#637=DIRECTION('',(-1.,0.,0.));
#638=AXIS2_PLACEMENT_3D('',#635,#636,#637);
#639=CIRCLE('',#638,13.);
#640=CARTESIAN_POINT('',(48.,6.,-30.));
#641=VERTEX_POINT('',#640);
#642=EDGE_CURVE('E428',#641,#616,#639,.F.);
#643=ORIENTED_EDGE('',*,*,#642,.F.);
#644=DIRECTION('',(-1.,0.,0.));
#645=VECTOR('',#644,1.);
#646=CARTESIAN_POINT('',(50.,6.,-30.));
#647=LINE('',#646,#645);
#648=EDGE_CURVE('E363',#641,#444,#647,.F.);
#649=ORIENTED_EDGE('',*,*,#648,.T.);
#650=EDGE_LOOP('',(#633,#634,#643,#649));
#651=FACE_BOUND('',#650,.T.);
#652=ADVANCED_FACE('F669',(#651),#632,.F.);
#653=CARTESIAN_POINT('',(50.,21.,30.));
#654=DIRECTION('',(0.,0.,-1.));
#655=DIRECTION('',(0.,-1.,0.));
#656=AXIS2_PLACEMENT_3D('',#653,#654,#655);
#657=PLANE('',#656);
#658=ORIENTED_EDGE('',*,*,#487,.T.);
#659=ORIENTED_EDGE('',*,*,#310,.F.);
#660=DIRECTION('',(0.,1.,0.));
#661=VECTOR('',#660,1.);
#662=CARTESIAN_POINT('',(49.,-1.,30.));
#663=LINE('',#662,#661);
#664=CARTESIAN_POINT('',(49.,-1.,30.));
#665=VERTEX_POINT('',#664);
#666=EDGE_CURVE('E261',#665,#301,#663,.T.);
#667=ORIENTED_EDGE('',*,*,#666,.F.);
#668=DIRECTION('',(-1.,0.,0.));
#669=VECTOR('',#668,1.);
#670=CARTESIAN_POINT('',(49.,-1.,30.));
#671=LINE('',#670,#669);
#672=CARTESIAN_POINT('',(48.,-1.,30.));
#673=VERTEX_POINT('',#672);
#674=EDGE_CURVE('E288',#665,#673,#671,.T.);
#675=ORIENTED_EDGE('',*,*,#674,.T.);
#676=DIRECTION('',(0.,-1.,0.));
#677=VECTOR('',#676,1.);
#678=CARTESIAN_POINT('',(48.,21.,30.));
#679=LINE('',#678,#677);
#680=EDGE_CURVE('E427',#583,#673,#679,.T.);
#681=ORIENTED_EDGE('',*,*,#680,.F.);
#682=ORIENTED_EDGE('',*,*,#584,.T.);
#683=EDGE_LOOP('',(#658,#659,#667,#675,#681,#682));
#684=FACE_BOUND('',#683,.T.);
#685=ADVANCED_FACE('F687',(#684),#657,.T.);
#686=CARTESIAN_POINT('',(50.,21.,-30.));
#687=DIRECTION('',(0.,0.,-1.));
#688=DIRECTION('',(0.,-1.,0.));
#689=AXIS2_PLACEMENT_3D('',#686,#687,#688);
#690=PLANE('',#689);
#691=ORIENTED_EDGE('',*,*,#468,.T.);
#692=ORIENTED_EDGE('',*,*,#648,.F.);
#693=DIRECTION('',(0.,-1.,0.));
#694=VECTOR('',#693,1.);
#695=CARTESIAN_POINT('',(48.,21.,-30.));
#696=LINE('',#695,#694);
#697=CARTESIAN_POINT('',(48.,-1.,-30.));
#698=VERTEX_POINT('',#697);
#699=EDGE_CURVE('E265',#698,#641,#696,.F.);
#700=ORIENTED_EDGE('',*,*,#699,.F.);
#701=DIRECTION('',(1.,0.,0.));
#702=VECTOR('',#701,1.);
#703=CARTESIAN_POINT('',(48.,-1.,-30.));
#704=LINE('',#703,#702);
#705=CARTESIAN_POINT('',(49.,-1.,-30.));
#706=VERTEX_POINT('',#705);
#707=EDGE_CURVE('E248',#698,#706,#704,.T.);
#708=ORIENTED_EDGE('',*,*,#707,.T.);
#709=DIRECTION('',(0.,1.,0.));
#710=VECTOR('',#709,1.);
#711=CARTESIAN_POINT('',(49.,-1.,-30.));
#712=LINE('',#711,#710);
#713=EDGE_CURVE('E257',#706,#250,#712,.T.);
#714=ORIENTED_EDGE('',*,*,#713,.T.);
#715=ORIENTED_EDGE('',*,*,#349,.T.);
#716=EDGE_LOOP('',(#691,#692,#700,#708,#714,#715));
#717=FACE_BOUND('',#716,.T.);
#718=ADVANCED_FACE('F263',(#717),#690,.F.);
#719=CARTESIAN_POINT('',(-50.,21.,-33.));
#720=DIRECTION('',(0.,0.,1.));
#721=DIRECTION('',(1.,0.,0.));
#722=AXIS2_PLACEMENT_3D('',#719,#720,#721);
#723=PLANE('',#722);
#724=CARTESIAN_POINT('',(35.,6.,-33.));
#725=DIRECTION('',(0.,0.,1.));
#726=DIRECTION('',(1.,0.,0.));
#727=AXIS2_PLACEMENT_3D('',#724,#725,#726);
#728=CIRCLE('',#727,10.);
#729=CARTESIAN_POINT('',(35.,16.,-33.));
#730=VERTEX_POINT('',#729);
#731=CARTESIAN_POINT('',(45.,6.00000000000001,-33.));
#732=VERTEX_POINT('',#731);
#733=EDGE_CURVE('E364',#730,#732,#728,.F.);
#734=ORIENTED_EDGE('',*,*,#733,.F.);
#735=DIRECTION('',(1.,0.,0.));
#736=VECTOR('',#735,1.);
#737=CARTESIAN_POINT('',(-50.,16.,-33.));
#738=LINE('',#737,#736);
#739=CARTESIAN_POINT('',(-35.,16.,-33.));
#740=VERTEX_POINT('',#739);
#741=EDGE_CURVE('E373',#740,#730,#738,.T.);
#742=ORIENTED_EDGE('',*,*,#741,.F.);
#743=CARTESIAN_POINT('',(-35.,6.,-33.));
#744=DIRECTION('',(0.,0.,1.));
#745=DIRECTION('',(1.,0.,0.));
#746=AXIS2_PLACEMENT_3D('',#743,#744,#745);
#747=CIRCLE('',#746,10.);
#748=CARTESIAN_POINT('',(-45.,6.00000000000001,-33.));
#749=VERTEX_POINT('',#748);
#750=EDGE_CURVE('E371',#749,#740,#747,.F.);
#751=ORIENTED_EDGE('',*,*,#750,.F.);
#752=DIRECTION('',(0.,1.,0.));
#753=VECTOR('',#752,1.);
#754=CARTESIAN_POINT('',(-45.,21.,-33.));
#755=LINE('',#754,#753);
#756=CARTESIAN_POINT('',(-45.,-1.,-33.));
#757=VERTEX_POINT('',#756);
#758=EDGE_CURVE('E367',#757,#749,#755,.T.);
#759=ORIENTED_EDGE('',*,*,#758,.F.);
#760=DIRECTION('',(1.,0.,0.));
#761=VECTOR('',#760,1.);
#762=CARTESIAN_POINT('',(45.,-1.,-33.));
#763=LINE('',#762,#761);
#764=CARTESIAN_POINT('',(45.,-1.,-33.));
#765=VERTEX_POINT('',#764);
#766=EDGE_CURVE('E268',#757,#765,#763,.T.);
#767=ORIENTED_EDGE('',*,*,#766,.T.);
#768=DIRECTION('',(0.,1.,0.));
#769=VECTOR('',#768,1.);
#770=CARTESIAN_POINT('',(45.,21.,-33.));
#771=LINE('',#770,#769);
#772=EDGE_CURVE('E366',#732,#765,#771,.F.);
#773=ORIENTED_EDGE('',*,*,#772,.F.);
#774=EDGE_LOOP('',(#734,#742,#751,#759,#767,#773));
#775=FACE_BOUND('',#774,.T.);
#776=ADVANCED_FACE('F728',(#775),#723,.T.);
#777=CARTESIAN_POINT('',(-48.,21.,35.));
#778=DIRECTION('',(1.,0.,0.));
#779=DIRECTION('',(0.,0.,-1.));
#780=AXIS2_PLACEMENT_3D('',#777,#778,#779);
#781=PLANE('',#780);
#782=DIRECTION('',(0.,0.,-1.));
#783=VECTOR('',#782,1.);
#784=CARTESIAN_POINT('',(-48.,6.00000000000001,35.));
#785=LINE('',#784,#783);
#786=CARTESIAN_POINT('',(-48.,6.00000000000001,30.));
#787=VERTEX_POINT('',#786);
#788=CARTESIAN_POINT('',(-48.,6.,-30.));
#789=VERTEX_POINT('',#788);
#790=EDGE_CURVE('E375',#787,#789,#785,.T.);
#791=ORIENTED_EDGE('',*,*,#790,.F.);
#792=DIRECTION('',(0.,1.,0.));
#793=VECTOR('',#792,1.);
#794=CARTESIAN_POINT('',(-48.,21.,30.));
#795=LINE('',#794,#793);
#796=CARTESIAN_POINT('',(-48.,-1.,30.));
#797=VERTEX_POINT('',#796);
#798=EDGE_CURVE('E369',#797,#787,#795,.T.);
#799=ORIENTED_EDGE('',*,*,#798,.F.);
#800=DIRECTION('',(0.,0.,-1.));
#801=VECTOR('',#800,1.);
#802=CARTESIAN_POINT('',(-48.,-1.,-30.));
#803=LINE('',#802,#801);
#804=CARTESIAN_POINT('',(-48.,-1.,-30.));
#805=VERTEX_POINT('',#804);
#806=EDGE_CURVE('E276',#797,#805,#803,.T.);
#807=ORIENTED_EDGE('',*,*,#806,.T.);
#808=DIRECTION('',(0.,1.,0.));
#809=VECTOR('',#808,1.);
#810=CARTESIAN_POINT('',(-48.,21.,-30.));
#811=LINE('',#810,#809);
#812=EDGE_CURVE('E376',#789,#805,#811,.F.);
#813=ORIENTED_EDGE('',*,*,#812,.F.);
#814=EDGE_LOOP('',(#791,#799,#807,#813));
#815=FACE_BOUND('',#814,.T.);
#816=ADVANCED_FACE('F740',(#815),#781,.T.);
#817=CARTESIAN_POINT('',(-50.,21.,33.));
#818=DIRECTION('',(0.,0.,-1.));
#819=DIRECTION('',(-1.,0.,0.));
#820=AXIS2_PLACEMENT_3D('',#817,#818,#819);
#821=PLANE('',#820);
#822=CARTESIAN_POINT('',(-35.,6.,33.));
#823=DIRECTION('',(0.,0.,-1.));
#824=DIRECTION('',(-1.,0.,0.));
#825=AXIS2_PLACEMENT_3D('',#822,#823,#824);
#826=CIRCLE('',#825,10.);
#827=CARTESIAN_POINT('',(-35.,16.,33.));
#828=VERTEX_POINT('',#827);
#829=CARTESIAN_POINT('',(-45.,6.00000000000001,33.));
#830=VERTEX_POINT('',#829);
#831=EDGE_CURVE('E417',#828,#830,#826,.F.);
#832=ORIENTED_EDGE('',*,*,#831,.F.);
#833=DIRECTION('',(-1.,0.,0.));
#834=VECTOR('',#833,1.);
#835=CARTESIAN_POINT('',(-50.,16.,33.));
#836=LINE('',#835,#834);
#837=CARTESIAN_POINT('',(35.,16.,33.));
#838=VERTEX_POINT('',#837);
#839=EDGE_CURVE('E391',#838,#828,#836,.T.);
#840=ORIENTED_EDGE('',*,*,#839,.F.);
#841=CARTESIAN_POINT('',(35.,6.,33.));
#842=DIRECTION('',(0.,0.,-1.));
#843=DIRECTION('',(-1.,0.,0.));
#844=AXIS2_PLACEMENT_3D('',#841,#842,#843);
#845=CIRCLE('',#844,10.);
#846=CARTESIAN_POINT('',(45.,6.00000000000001,33.));
#847=VERTEX_POINT('',#846);
#848=EDGE_CURVE('E414',#847,#838,#845,.F.);
#849=ORIENTED_EDGE('',*,*,#848,.F.);
#850=DIRECTION('',(0.,1.,0.));
#851=VECTOR('',#850,1.);
#852=CARTESIAN_POINT('',(45.,21.,33.));
#853=LINE('',#852,#851);
#854=CARTESIAN_POINT('',(45.,-1.,33.));
#855=VERTEX_POINT('',#854);
#856=EDGE_CURVE('E416',#855,#847,#853,.T.);
#857=ORIENTED_EDGE('',*,*,#856,.F.);
#858=DIRECTION('',(-1.,0.,0.));
#859=VECTOR('',#858,1.);
#860=CARTESIAN_POINT('',(-45.,-1.,33.));
#861=LINE('',#860,#859);
#862=CARTESIAN_POINT('',(-45.,-1.,33.));
#863=VERTEX_POINT('',#862);
#864=EDGE_CURVE('E282',#855,#863,#861,.T.);
#865=ORIENTED_EDGE('',*,*,#864,.T.);
#866=DIRECTION('',(0.,1.,0.));
#867=VECTOR('',#866,1.);
#868=CARTESIAN_POINT('',(-45.,21.,33.));
#869=LINE('',#868,#867);
#870=EDGE_CURVE('E398',#830,#863,#869,.F.);
#871=ORIENTED_EDGE('',*,*,#870,.F.);
#872=EDGE_LOOP('',(#832,#840,#849,#857,#865,#871));
#873=FACE_BOUND('',#872,.T.);
#874=ADVANCED_FACE('F700',(#873),#821,.T.);
#875=CARTESIAN_POINT('',(0.,19.,0.));
#876=DIRECTION('',(0.,-1.,0.));
#877=DIRECTION('',(0.,0.,-1.));
#878=AXIS2_PLACEMENT_3D('',#875,#876,#877);
#879=PLANE('',#878);
#880=CARTESIAN_POINT('',(-25.,19.,0.));
#881=DIRECTION('',(0.,-1.,0.));
#882=DIRECTION('',(0.,0.,-1.));
#883=AXIS2_PLACEMENT_3D('',#880,#881,#882);
#884=CIRCLE('',#883,5.05368379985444);
#885=CARTESIAN_POINT('',(-25.,19.,-5.05368379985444));
#886=VERTEX_POINT('',#885);
#887=EDGE_CURVE('E44',#886,#886,#884,.F.);
#888=ORIENTED_EDGE('',*,*,#887,.T.);
#889=EDGE_LOOP('',(#888));
#890=FACE_BOUND('',#889,.T.);
#891=CARTESIAN_POINT('',(9.99999999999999,19.,0.));
#892=DIRECTION('',(0.,-1.,0.));
#893=DIRECTION('',(0.,0.,-1.));
#894=AXIS2_PLACEMENT_3D('',#891,#892,#893);
#895=CIRCLE('',#894,5.05368379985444);
#896=CARTESIAN_POINT('',(9.99999999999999,19.,-5.05368379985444));
#897=VERTEX_POINT('',#896);
#898=EDGE_CURVE('E548',#897,#897,#895,.F.);
#899=ORIENTED_EDGE('',*,*,#898,.T.);
#900=EDGE_LOOP('',(#899));
#901=FACE_BOUND('',#900,.T.);
#902=ORIENTED_EDGE('',*,*,#617,.F.);
#903=DIRECTION('',(1.,0.,0.));
#904=VECTOR('',#903,1.);
#905=CARTESIAN_POINT('',(0.,19.,30.));
#906=LINE('',#905,#904);
#907=CARTESIAN_POINT('',(-35.,19.,30.));
#908=VERTEX_POINT('',#907);
#909=EDGE_CURVE('E395',#908,#592,#906,.T.);
#910=ORIENTED_EDGE('',*,*,#909,.F.);
#911=DIRECTION('',(0.,0.,-1.));
#912=VECTOR('',#911,1.);
#913=CARTESIAN_POINT('',(-35.,19.,0.));
#914=LINE('',#913,#912);
#915=CARTESIAN_POINT('',(-35.,19.,-30.));
#916=VERTEX_POINT('',#915);
#917=EDGE_CURVE('E382',#916,#908,#914,.F.);
#918=ORIENTED_EDGE('',*,*,#917,.F.);
#919=DIRECTION('',(1.,0.,0.));
#920=VECTOR('',#919,1.);
#921=CARTESIAN_POINT('',(0.,19.,-30.));
#922=LINE('',#921,#920);
#923=EDGE_CURVE('E393',#616,#916,#922,.F.);
#924=ORIENTED_EDGE('',*,*,#923,.F.);
#925=EDGE_LOOP('',(#902,#910,#918,#924));
#926=FACE_BOUND('',#925,.T.);
#927=ADVANCED_FACE('F553',(#890,#901,#926),#879,.T.);
#928=CARTESIAN_POINT('',(-35.,6.,0.));
#929=DIRECTION('',(0.,0.,1.));
#930=DIRECTION('',(1.,0.,0.));
#931=AXIS2_PLACEMENT_3D('',#928,#929,#930);
#932=CYLINDRICAL_SURFACE('',#931,13.);
#933=ORIENTED_EDGE('',*,*,#917,.T.);
#934=CARTESIAN_POINT('',(-35.,6.,30.));
#935=DIRECTION('',(0.,0.,1.));
#936=DIRECTION('',(1.,0.,0.));
#937=AXIS2_PLACEMENT_3D('',#934,#935,#936);
#938=CIRCLE('',#937,13.);
#939=EDGE_CURVE('E378',#787,#908,#938,.F.);
#940=ORIENTED_EDGE('',*,*,#939,.F.);
#941=ORIENTED_EDGE('',*,*,#790,.T.);
#942=CARTESIAN_POINT('',(-35.,6.,-30.));
#943=DIRECTION('',(0.,0.,1.));
#944=DIRECTION('',(1.,0.,0.));
#945=AXIS2_PLACEMENT_3D('',#942,#943,#944);
#946=CIRCLE('',#945,13.);
#947=EDGE_CURVE('E389',#916,#789,#946,.T.);
#948=ORIENTED_EDGE('',*,*,#947,.F.);
#949=EDGE_LOOP('',(#933,#940,#941,#948));
#950=FACE_BOUND('',#949,.T.);
#951=ADVANCED_FACE('F713',(#950),#932,.F.);
#952=CARTESIAN_POINT('',(-45.,21.,-30.));
#953=DIRECTION('',(0.,-1.,0.));
#954=DIRECTION('',(0.,0.,-1.));
#955=AXIS2_PLACEMENT_3D('',#952,#953,#954);
#956=CYLINDRICAL_SURFACE('',#955,3.);
#957=ORIENTED_EDGE('',*,*,#812,.T.);
#958=CARTESIAN_POINT('',(-45.,-1.,-30.));
#959=DIRECTION('',(0.,-1.,0.));
#960=DIRECTION('',(0.,0.,-1.));
#961=AXIS2_PLACEMENT_3D('',#958,#959,#960);
#962=CIRCLE('',#961,3.00000000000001);
#963=EDGE_CURVE('E273',#805,#757,#962,.T.);
#964=ORIENTED_EDGE('',*,*,#963,.T.);
#965=ORIENTED_EDGE('',*,*,#758,.T.);
#966=CARTESIAN_POINT('',(-45.,6.,-30.));
#967=DIRECTION('',(0.,1.,0.));
#968=DIRECTION('',(-1.,0.,0.));
#969=AXIS2_PLACEMENT_3D('',#966,#967,#968);
#970=CIRCLE('',#969,3.);
#971=EDGE_CURVE('E379',#749,#789,#970,.T.);
#972=ORIENTED_EDGE('',*,*,#971,.T.);
#973=EDGE_LOOP('',(#957,#964,#965,#972));
#974=FACE_BOUND('',#973,.T.);
#975=ADVANCED_FACE('F735',(#974),#956,.F.);
#976=CARTESIAN_POINT('',(-35.,6.,-30.));
#977=DIRECTION('',(0.,0.,1.));
#978=DIRECTION('',(1.,0.,0.));
#979=AXIS2_PLACEMENT_3D('',#976,#977,#978);
#980=TOROIDAL_SURFACE('',#979,10.,3.);
#981=ORIENTED_EDGE('',*,*,#971,.F.);
#982=ORIENTED_EDGE('',*,*,#750,.T.);
#983=CARTESIAN_POINT('',(-35.,16.,-30.));
#984=DIRECTION('',(-1.,0.,0.));
#985=DIRECTION('',(0.,0.,1.));
#986=AXIS2_PLACEMENT_3D('',#983,#984,#985);
#987=CIRCLE('',#986,3.);
#988=EDGE_CURVE('E383',#740,#916,#987,.F.);
#989=ORIENTED_EDGE('',*,*,#988,.T.);
#990=ORIENTED_EDGE('',*,*,#947,.T.);
#991=EDGE_LOOP('',(#981,#982,#989,#990));
#992=FACE_BOUND('',#991,.T.);
#993=ADVANCED_FACE('F827',(#992),#980,.F.);
#994=CARTESIAN_POINT('',(0.,16.,-30.));
#995=DIRECTION('',(-1.,0.,0.));
#996=DIRECTION('',(0.,0.,1.));
#997=AXIS2_PLACEMENT_3D('',#994,#995,#996);
#998=CYLINDRICAL_SURFACE('',#997,3.);
#999=ORIENTED_EDGE('',*,*,#988,.F.);
#1000=ORIENTED_EDGE('',*,*,#741,.T.);
#1001=CARTESIAN_POINT('',(35.,16.,-30.));
#1002=DIRECTION('',(1.,0.,0.));
#1003=DIRECTION('',(0.,1.,0.));
#1004=AXIS2_PLACEMENT_3D('',#1001,#1002,#1003);
#1005=CIRCLE('',#1004,3.);
#1006=EDGE_CURVE('E401',#730,#616,#1005,.T.);
#1007=ORIENTED_EDGE('',*,*,#1006,.T.);
#1008=ORIENTED_EDGE('',*,*,#923,.T.);
#1009=EDGE_LOOP('',(#999,#1000,#1007,#1008));
#1010=FACE_BOUND('',#1009,.T.);
#1011=ADVANCED_FACE('F830',(#1010),#998,.F.);
#1012=CARTESIAN_POINT('',(35.,6.,-30.));
#1013=DIRECTION('',(0.,0.,1.));
#1014=DIRECTION('',(1.,0.,0.));
#1015=AXIS2_PLACEMENT_3D('',#1012,#1013,#1014);
#1016=TOROIDAL_SURFACE('',#1015,10.,3.);
#1017=ORIENTED_EDGE('',*,*,#1006,.F.);
#1018=ORIENTED_EDGE('',*,*,#733,.T.);
#1019=CARTESIAN_POINT('',(45.,6.,-30.));
#1020=DIRECTION('',(0.,-1.,0.));
#1021=DIRECTION('',(0.,0.,-1.));
#1022=AXIS2_PLACEMENT_3D('',#1019,#1020,#1021);
#1023=CIRCLE('',#1022,3.);
#1024=EDGE_CURVE('E404',#732,#641,#1023,.T.);
#1025=ORIENTED_EDGE('',*,*,#1024,.T.);
#1026=ORIENTED_EDGE('',*,*,#642,.T.);
#1027=EDGE_LOOP('',(#1017,#1018,#1025,#1026));
#1028=FACE_BOUND('',#1027,.T.);
#1029=ADVANCED_FACE('F721',(#1028),#1016,.F.);
#1030=CARTESIAN_POINT('',(45.,21.,-30.));
#1031=DIRECTION('',(0.,-1.,0.));
#1032=DIRECTION('',(0.,0.,-1.));
#1033=AXIS2_PLACEMENT_3D('',#1030,#1031,#1032);
#1034=CYLINDRICAL_SURFACE('',#1033,3.);
#1035=ORIENTED_EDGE('',*,*,#1024,.F.);
#1036=ORIENTED_EDGE('',*,*,#772,.T.);
#1037=CARTESIAN_POINT('',(45.,-1.,-30.));
#1038=DIRECTION('',(0.,-1.,0.));
#1039=DIRECTION('',(0.,0.,-1.));
#1040=AXIS2_PLACEMENT_3D('',#1037,#1038,#1039);
#1041=CIRCLE('',#1040,3.);
#1042=EDGE_CURVE('E266',#765,#698,#1041,.T.);
#1043=ORIENTED_EDGE('',*,*,#1042,.T.);
#1044=ORIENTED_EDGE('',*,*,#699,.T.);
#1045=EDGE_LOOP('',(#1035,#1036,#1043,#1044));
#1046=FACE_BOUND('',#1045,.T.);
#1047=ADVANCED_FACE('F726',(#1046),#1034,.F.);
#1048=CARTESIAN_POINT('',(45.,21.,30.));
#1049=DIRECTION('',(0.,-1.,0.));
#1050=DIRECTION('',(0.,0.,-1.));
#1051=AXIS2_PLACEMENT_3D('',#1048,#1049,#1050);
#1052=CYLINDRICAL_SURFACE('',#1051,3.);
#1053=ORIENTED_EDGE('',*,*,#680,.T.);
#1054=CARTESIAN_POINT('',(45.,-1.,30.));
#1055=DIRECTION('',(0.,-1.,0.));
#1056=DIRECTION('',(0.,0.,-1.));
#1057=AXIS2_PLACEMENT_3D('',#1054,#1055,#1056);
#1058=CIRCLE('',#1057,3.);
#1059=EDGE_CURVE('E285',#673,#855,#1058,.T.);
#1060=ORIENTED_EDGE('',*,*,#1059,.T.);
#1061=ORIENTED_EDGE('',*,*,#856,.T.);
#1062=CARTESIAN_POINT('',(45.,6.,30.));
#1063=DIRECTION('',(0.,1.,0.));
#1064=DIRECTION('',(-1.,0.,0.));
#1065=AXIS2_PLACEMENT_3D('',#1062,#1063,#1064);
#1066=CIRCLE('',#1065,3.);
#1067=EDGE_CURVE('E407',#847,#583,#1066,.T.);
#1068=ORIENTED_EDGE('',*,*,#1067,.T.);
#1069=EDGE_LOOP('',(#1053,#1060,#1061,#1068));
#1070=FACE_BOUND('',#1069,.T.);
#1071=ADVANCED_FACE('F692',(#1070),#1052,.F.);
#1072=CARTESIAN_POINT('',(35.,6.,30.));
#1073=DIRECTION('',(0.,0.,-1.));
#1074=DIRECTION('',(-1.,0.,0.));
#1075=AXIS2_PLACEMENT_3D('',#1072,#1073,#1074);
#1076=TOROIDAL_SURFACE('',#1075,10.,3.);
#1077=ORIENTED_EDGE('',*,*,#1067,.F.);
#1078=ORIENTED_EDGE('',*,*,#848,.T.);
#1079=CARTESIAN_POINT('',(35.,16.,30.));
#1080=DIRECTION('',(1.,0.,0.));
#1081=DIRECTION('',(0.,0.,-1.));
#1082=AXIS2_PLACEMENT_3D('',#1079,#1080,#1081);
#1083=CIRCLE('',#1082,3.);
#1084=EDGE_CURVE('E410',#838,#592,#1083,.F.);
#1085=ORIENTED_EDGE('',*,*,#1084,.T.);
#1086=ORIENTED_EDGE('',*,*,#593,.T.);
#1087=EDGE_LOOP('',(#1077,#1078,#1085,#1086));
#1088=FACE_BOUND('',#1087,.T.);
#1089=ADVANCED_FACE('F695',(#1088),#1076,.F.);
#1090=CARTESIAN_POINT('',(0.,16.,30.));
#1091=DIRECTION('',(1.,0.,0.));
#1092=DIRECTION('',(0.,0.,-1.));
#1093=AXIS2_PLACEMENT_3D('',#1090,#1091,#1092);
#1094=CYLINDRICAL_SURFACE('',#1093,3.);
#1095=ORIENTED_EDGE('',*,*,#1084,.F.);
#1096=ORIENTED_EDGE('',*,*,#839,.T.);
#1097=CARTESIAN_POINT('',(-35.,16.,30.));
#1098=DIRECTION('',(-1.,0.,0.));
#1099=DIRECTION('',(0.,-1.,0.));
#1100=AXIS2_PLACEMENT_3D('',#1097,#1098,#1099);
#1101=CIRCLE('',#1100,3.);
#1102=EDGE_CURVE('E413',#828,#908,#1101,.T.);
#1103=ORIENTED_EDGE('',*,*,#1102,.T.);
#1104=ORIENTED_EDGE('',*,*,#909,.T.);
#1105=EDGE_LOOP('',(#1095,#1096,#1103,#1104));
#1106=FACE_BOUND('',#1105,.T.);
#1107=ADVANCED_FACE('F705',(#1106),#1094,.F.);
#1108=CARTESIAN_POINT('',(-35.,6.,30.));
#1109=DIRECTION('',(0.,0.,-1.));
#1110=DIRECTION('',(-1.,0.,0.));
#1111=AXIS2_PLACEMENT_3D('',#1108,#1109,#1110);
#1112=TOROIDAL_SURFACE('',#1111,10.,3.);
#1113=ORIENTED_EDGE('',*,*,#1102,.F.);
#1114=ORIENTED_EDGE('',*,*,#831,.T.);
#1115=CARTESIAN_POINT('',(-45.,6.,30.));
#1116=DIRECTION('',(0.,-1.,0.));
#1117=DIRECTION('',(0.,0.,-1.));
#1118=AXIS2_PLACEMENT_3D('',#1115,#1116,#1117);
#1119=CIRCLE('',#1118,3.);
#1120=EDGE_CURVE('E356',#830,#787,#1119,.T.);
#1121=ORIENTED_EDGE('',*,*,#1120,.T.);
#1122=ORIENTED_EDGE('',*,*,#939,.T.);
#1123=EDGE_LOOP('',(#1113,#1114,#1121,#1122));
#1124=FACE_BOUND('',#1123,.T.);
#1125=ADVANCED_FACE('F577',(#1124),#1112,.F.);
#1126=CARTESIAN_POINT('',(-45.,21.,30.));
#1127=DIRECTION('',(0.,-1.,0.));
#1128=DIRECTION('',(0.,0.,-1.));
#1129=AXIS2_PLACEMENT_3D('',#1126,#1127,#1128);
#1130=CYLINDRICAL_SURFACE('',#1129,3.);
#1131=ORIENTED_EDGE('',*,*,#1120,.F.);
#1132=ORIENTED_EDGE('',*,*,#870,.T.);
#1133=CARTESIAN_POINT('',(-45.,-1.,30.));
#1134=DIRECTION('',(0.,-1.,0.));
#1135=DIRECTION('',(0.,0.,-1.));
#1136=AXIS2_PLACEMENT_3D('',#1133,#1134,#1135);
#1137=CIRCLE('',#1136,3.);
#1138=EDGE_CURVE('E279',#863,#797,#1137,.T.);
#1139=ORIENTED_EDGE('',*,*,#1138,.T.);
#1140=ORIENTED_EDGE('',*,*,#798,.T.);
#1141=EDGE_LOOP('',(#1131,#1132,#1139,#1140));
#1142=FACE_BOUND('',#1141,.T.);
#1143=ADVANCED_FACE('F571',(#1142),#1130,.F.);
#1144=CARTESIAN_POINT('',(-25.,6.,0.));
#1145=DIRECTION('',(0.,1.,0.));
#1146=DIRECTION('',(0.,0.,1.));
#1147=AXIS2_PLACEMENT_3D('',#1144,#1145,#1146);
#1148=PLANE('',#1147);
#1149=CARTESIAN_POINT('',(-25.,6.,0.));
#1150=DIRECTION('',(0.,1.,0.));
#1151=DIRECTION('',(0.,0.,1.));
#1152=AXIS2_PLACEMENT_3D('',#1149,#1150,#1151);
#1153=CIRCLE('',#1152,1.95);
#1154=CARTESIAN_POINT('',(-25.,6.,1.95));
#1155=VERTEX_POINT('',#1154);
#1156=EDGE_CURVE('E342',#1155,#1155,#1153,.T.);
#1157=ORIENTED_EDGE('',*,*,#1156,.T.);
#1158=EDGE_LOOP('',(#1157));
#1159=FACE_BOUND('',#1158,.T.);
#1160=CARTESIAN_POINT('',(-25.,6.,0.));
#1161=DIRECTION('',(0.,1.,0.));
#1162=DIRECTION('',(0.,0.,1.));
#1163=AXIS2_PLACEMENT_3D('',#1160,#1161,#1162);
#1164=CIRCLE('',#1163,3.);
#1165=CARTESIAN_POINT('',(-25.,6.,3.));
#1166=VERTEX_POINT('',#1165);
#1167=EDGE_CURVE('E353',#1166,#1166,#1164,.T.);
#1168=ORIENTED_EDGE('',*,*,#1167,.F.);
#1169=EDGE_LOOP('',(#1168));
#1170=FACE_BOUND('',#1169,.T.);
#1171=ADVANCED_FACE('F566',(#1159,#1170),#1148,.F.);
#1172=CARTESIAN_POINT('',(-25.,6.,0.));
#1173=DIRECTION('',(0.,1.,0.));
#1174=DIRECTION('',(0.,0.,1.));
#1175=AXIS2_PLACEMENT_3D('',#1172,#1173,#1174);
#1176=CONICAL_SURFACE('',#1175,3.,0.0872664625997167);
#1177=CARTESIAN_POINT('',(-25.,18.0871557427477,0.));
#1178=DIRECTION('',(0.,-1.,0.));
#1179=DIRECTION('',(0.,0.,-1.));
#1180=AXIS2_PLACEMENT_3D('',#1177,#1178,#1179);
#1181=CIRCLE('',#1180,4.05748910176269);
#1182=CARTESIAN_POINT('',(-25.,18.0871557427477,-4.05748910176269));
#1183=VERTEX_POINT('',#1182);
#1184=EDGE_CURVE('E519',#1183,#1183,#1181,.T.);
#1185=ORIENTED_EDGE('',*,*,#1184,.T.);
#1186=EDGE_LOOP('',(#1185));
#1187=FACE_BOUND('',#1186,.T.);
#1188=ORIENTED_EDGE('',*,*,#1167,.T.);
#1189=EDGE_LOOP('',(#1188));
#1190=FACE_BOUND('',#1189,.T.);
#1191=ADVANCED_FACE('F562',(#1187,#1190),#1176,.T.);
#1192=CARTESIAN_POINT('',(9.99999999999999,6.,0.));
#1193=DIRECTION('',(0.,1.,0.));
#1194=DIRECTION('',(0.,0.,1.));
#1195=AXIS2_PLACEMENT_3D('',#1192,#1193,#1194);
#1196=PLANE('',#1195);
#1197=CARTESIAN_POINT('',(9.99999999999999,6.,0.));
#1198=DIRECTION('',(0.,1.,0.));
#1199=DIRECTION('',(0.,0.,1.));
#1200=AXIS2_PLACEMENT_3D('',#1197,#1198,#1199);
#1201=CIRCLE('',#1200,1.95);
#1202=CARTESIAN_POINT('',(9.99999999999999,6.,1.95));
#1203=VERTEX_POINT('',#1202);
#1204=EDGE_CURVE('E349',#1203,#1203,#1201,.T.);
#1205=ORIENTED_EDGE('',*,*,#1204,.T.);
#1206=EDGE_LOOP('',(#1205));
#1207=FACE_BOUND('',#1206,.T.);
#1208=CARTESIAN_POINT('',(9.99999999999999,6.,0.));
#1209=DIRECTION('',(0.,1.,0.));
#1210=DIRECTION('',(0.,0.,1.));
#1211=AXIS2_PLACEMENT_3D('',#1208,#1209,#1210);
#1212=CIRCLE('',#1211,3.);
#1213=CARTESIAN_POINT('',(9.99999999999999,6.,3.));
#1214=VERTEX_POINT('',#1213);
#1215=EDGE_CURVE('E350',#1214,#1214,#1212,.T.);
#1216=ORIENTED_EDGE('',*,*,#1215,.F.);
#1217=EDGE_LOOP('',(#1216));
#1218=FACE_BOUND('',#1217,.T.);
#1219=ADVANCED_FACE('F565',(#1207,#1218),#1196,.F.);
#1220=CARTESIAN_POINT('',(9.99999999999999,6.,0.));
#1221=DIRECTION('',(0.,1.,0.));
#1222=DIRECTION('',(0.,0.,1.));
#1223=AXIS2_PLACEMENT_3D('',#1220,#1221,#1222);
#1224=CONICAL_SURFACE('',#1223,3.,0.0872664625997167);
#1225=CARTESIAN_POINT('',(9.99999999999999,18.0871557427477,0.));
#1226=DIRECTION('',(0.,-1.,0.));
#1227=DIRECTION('',(0.,0.,-1.));
#1228=AXIS2_PLACEMENT_3D('',#1225,#1226,#1227);
#1229=CIRCLE('',#1228,4.05748910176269);
#1230=CARTESIAN_POINT('',(9.99999999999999,18.0871557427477,-4.05748910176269));
#1231=VERTEX_POINT('',#1230);
#1232=EDGE_CURVE('E11',#1231,#1231,#1229,.T.);
#1233=ORIENTED_EDGE('',*,*,#1232,.T.);
#1234=EDGE_LOOP('',(#1233));
#1235=FACE_BOUND('',#1234,.T.);
#1236=ORIENTED_EDGE('',*,*,#1215,.T.);
#1237=EDGE_LOOP('',(#1236));
#1238=FACE_BOUND('',#1237,.T.);
#1239=ADVANCED_FACE('F797',(#1235,#1238),#1224,.T.);
#1240=CARTESIAN_POINT('',(9.99999999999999,21.,0.));
#1241=DIRECTION('',(0.,1.,0.));
#1242=DIRECTION('',(0.,0.,1.));
#1243=AXIS2_PLACEMENT_3D('',#1240,#1241,#1242);
#1244=CYLINDRICAL_SURFACE('',#1243,1.95);
#1245=CARTESIAN_POINT('',(9.99999999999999,18.85,0.));
#1246=DIRECTION('',(0.,1.,0.));
#1247=DIRECTION('',(0.,0.,1.));
#1248=AXIS2_PLACEMENT_3D('',#1245,#1246,#1247);
#1249=CIRCLE('',#1248,1.95);
#1250=CARTESIAN_POINT('',(9.99999999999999,18.85,1.95));
#1251=VERTEX_POINT('',#1250);
#1252=EDGE_CURVE('E346',#1251,#1251,#1249,.T.);
#1253=ORIENTED_EDGE('',*,*,#1252,.T.);
#1254=EDGE_LOOP('',(#1253));
#1255=FACE_BOUND('',#1254,.T.);
#1256=ORIENTED_EDGE('',*,*,#1204,.F.);
#1257=EDGE_LOOP('',(#1256));
#1258=FACE_BOUND('',#1257,.T.);
#1259=ADVANCED_FACE('F793',(#1255,#1258),#1244,.F.);
#1260=CARTESIAN_POINT('',(9.99999999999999,21.,0.));
#1261=DIRECTION('',(0.,1.,0.));
#1262=DIRECTION('',(0.,0.,1.));
#1263=AXIS2_PLACEMENT_3D('',#1260,#1261,#1262);
#1264=CONICAL_SURFACE('',#1263,4.1,0.785398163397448);
#1265=ORIENTED_EDGE('',*,*,#1252,.F.);
#1266=EDGE_LOOP('',(#1265));
#1267=FACE_BOUND('',#1266,.T.);
#1268=ORIENTED_EDGE('',*,*,#198,.T.);
#1269=EDGE_LOOP('',(#1268));
#1270=FACE_BOUND('',#1269,.T.);
#1271=ADVANCED_FACE('F789',(#1267,#1270),#1264,.F.);
#1272=CARTESIAN_POINT('',(-25.,21.,0.));
#1273=DIRECTION('',(0.,1.,0.));
#1274=DIRECTION('',(0.,0.,1.));
#1275=AXIS2_PLACEMENT_3D('',#1272,#1273,#1274);
#1276=CYLINDRICAL_SURFACE('',#1275,1.95);
#1277=CARTESIAN_POINT('',(-25.,18.85,0.));
#1278=DIRECTION('',(0.,1.,0.));
#1279=DIRECTION('',(0.,0.,1.));
#1280=AXIS2_PLACEMENT_3D('',#1277,#1278,#1279);
#1281=CIRCLE('',#1280,1.95);
#1282=CARTESIAN_POINT('',(-25.,18.85,1.95));
#1283=VERTEX_POINT('',#1282);
#1284=EDGE_CURVE('E339',#1283,#1283,#1281,.T.);
#1285=ORIENTED_EDGE('',*,*,#1284,.T.);
#1286=EDGE_LOOP('',(#1285));
#1287=FACE_BOUND('',#1286,.T.);
#1288=ORIENTED_EDGE('',*,*,#1156,.F.);
#1289=EDGE_LOOP('',(#1288));
#1290=FACE_BOUND('',#1289,.T.);
#1291=ADVANCED_FACE('F785',(#1287,#1290),#1276,.F.);
#1292=CARTESIAN_POINT('',(-25.,21.,0.));
#1293=DIRECTION('',(0.,1.,0.));
#1294=DIRECTION('',(0.,0.,1.));
#1295=AXIS2_PLACEMENT_3D('',#1292,#1293,#1294);
#1296=CONICAL_SURFACE('',#1295,4.1,0.785398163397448);
#1297=ORIENTED_EDGE('',*,*,#1284,.F.);
#1298=EDGE_LOOP('',(#1297));
#1299=FACE_BOUND('',#1298,.T.);
#1300=ORIENTED_EDGE('',*,*,#187,.T.);
#1301=EDGE_LOOP('',(#1300));
#1302=FACE_BOUND('',#1301,.T.);
#1303=ADVANCED_FACE('F559',(#1299,#1302),#1296,.F.);
#1304=CARTESIAN_POINT('',(-25.,18.,0.));
#1305=DIRECTION('',(0.,-1.,0.));
#1306=DIRECTION('',(0.,0.,-1.));
#1307=AXIS2_PLACEMENT_3D('',#1304,#1305,#1306);
#1308=TOROIDAL_SURFACE('',#1307,5.05368379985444,1.);
#1309=ORIENTED_EDGE('',*,*,#887,.F.);
#1310=EDGE_LOOP('',(#1309));
#1311=FACE_BOUND('',#1310,.T.);
#1312=ORIENTED_EDGE('',*,*,#1184,.F.);
#1313=EDGE_LOOP('',(#1312));
#1314=FACE_BOUND('',#1313,.T.);
#1315=ADVANCED_FACE('F556',(#1311,#1314),#1308,.F.);
#1316=CARTESIAN_POINT('',(9.99999999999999,18.,0.));
#1317=DIRECTION('',(0.,-1.,0.));
#1318=DIRECTION('',(0.,0.,-1.));
#1319=AXIS2_PLACEMENT_3D('',#1316,#1317,#1318);
#1320=TOROIDAL_SURFACE('',#1319,5.05368379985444,1.);
#1321=ORIENTED_EDGE('',*,*,#898,.F.);
#1322=EDGE_LOOP('',(#1321));
#1323=FACE_BOUND('',#1322,.T.);
#1324=ORIENTED_EDGE('',*,*,#1232,.F.);
#1325=EDGE_LOOP('',(#1324));
#1326=FACE_BOUND('',#1325,.T.);
#1327=ADVANCED_FACE('F38',(#1323,#1326),#1320,.F.);
#1328=CARTESIAN_POINT('',(45.,-1.,-30.));
#1329=DIRECTION('',(0.,1.,0.));
#1330=DIRECTION('',(0.,0.,1.));
#1331=AXIS2_PLACEMENT_3D('',#1328,#1329,#1330);
#1332=CYLINDRICAL_SURFACE('',#1331,4.);
#1333=ORIENTED_EDGE('',*,*,#251,.T.);
#1334=ORIENTED_EDGE('',*,*,#713,.F.);
#1335=CARTESIAN_POINT('',(45.,-1.,-30.));
#1336=DIRECTION('',(0.,-1.,0.));
#1337=DIRECTION('',(1.,0.,0.));
#1338=AXIS2_PLACEMENT_3D('',#1335,#1336,#1337);
#1339=CIRCLE('',#1338,4.);
#1340=CARTESIAN_POINT('',(45.,-1.,-34.));
#1341=VERTEX_POINT('',#1340);
#1342=EDGE_CURVE('E243',#1341,#706,#1339,.T.);
#1343=ORIENTED_EDGE('',*,*,#1342,.F.);
#1344=DIRECTION('',(0.,1.,0.));
#1345=VECTOR('',#1344,1.);
#1346=CARTESIAN_POINT('',(45.,-1.,-34.));
#1347=LINE('',#1346,#1345);
#1348=EDGE_CURVE('E302',#1341,#248,#1347,.T.);
#1349=ORIENTED_EDGE('',*,*,#1348,.T.);
#1350=EDGE_LOOP('',(#1333,#1334,#1343,#1349));
#1351=FACE_BOUND('',#1350,.T.);
#1352=ADVANCED_FACE('F258',(#1351),#1332,.T.);
#1353=CARTESIAN_POINT('',(45.,-1.,30.));
#1354=DIRECTION('',(0.,1.,0.));
#1355=DIRECTION('',(0.,0.,1.));
#1356=AXIS2_PLACEMENT_3D('',#1353,#1354,#1355);
#1357=CYLINDRICAL_SURFACE('',#1356,4.);
#1358=ORIENTED_EDGE('',*,*,#302,.T.);
#1359=DIRECTION('',(0.,1.,0.));
#1360=VECTOR('',#1359,1.);
#1361=CARTESIAN_POINT('',(45.,-1.,34.));
#1362=LINE('',#1361,#1360);
#1363=CARTESIAN_POINT('',(45.,-1.,34.));
#1364=VERTEX_POINT('',#1363);
#1365=EDGE_CURVE('E332',#1364,#292,#1362,.T.);
#1366=ORIENTED_EDGE('',*,*,#1365,.F.);
#1367=CARTESIAN_POINT('',(45.,-1.,30.));
#1368=DIRECTION('',(0.,-1.,0.));
#1369=DIRECTION('',(1.,0.,0.));
#1370=AXIS2_PLACEMENT_3D('',#1367,#1368,#1369);
#1371=CIRCLE('',#1370,4.);
#1372=EDGE_CURVE('E291',#665,#1364,#1371,.T.);
#1373=ORIENTED_EDGE('',*,*,#1372,.F.);
#1374=ORIENTED_EDGE('',*,*,#666,.T.);
#1375=EDGE_LOOP('',(#1358,#1366,#1373,#1374));
#1376=FACE_BOUND('',#1375,.T.);
#1377=ADVANCED_FACE('F747',(#1376),#1357,.T.);
#1378=CARTESIAN_POINT('',(-45.,-1.,34.));
#1379=DIRECTION('',(0.,0.,-1.));
#1380=DIRECTION('',(-1.,0.,0.));
#1381=AXIS2_PLACEMENT_3D('',#1378,#1379,#1380);
#1382=PLANE('',#1381);
#1383=ORIENTED_EDGE('',*,*,#293,.T.);
#1384=DIRECTION('',(0.,1.,0.));
#1385=VECTOR('',#1384,1.);
#1386=CARTESIAN_POINT('',(-45.,-1.,34.));
#1387=LINE('',#1386,#1385);
#1388=CARTESIAN_POINT('',(-45.,-1.,34.));
#1389=VERTEX_POINT('',#1388);
#1390=EDGE_CURVE('E329',#1389,#284,#1387,.T.);
#1391=ORIENTED_EDGE('',*,*,#1390,.F.);
#1392=DIRECTION('',(-1.,0.,0.));
#1393=VECTOR('',#1392,1.);
#1394=CARTESIAN_POINT('',(-45.,-1.,34.));
#1395=LINE('',#1394,#1393);
#1396=EDGE_CURVE('E293',#1364,#1389,#1395,.T.);
#1397=ORIENTED_EDGE('',*,*,#1396,.F.);
#1398=ORIENTED_EDGE('',*,*,#1365,.T.);
#1399=EDGE_LOOP('',(#1383,#1391,#1397,#1398));
#1400=FACE_BOUND('',#1399,.T.);
#1401=ADVANCED_FACE('F749',(#1400),#1382,.F.);
#1402=CARTESIAN_POINT('',(-45.,-1.,30.));
#1403=DIRECTION('',(0.,1.,0.));
#1404=DIRECTION('',(0.,0.,1.));
#1405=AXIS2_PLACEMENT_3D('',#1402,#1403,#1404);
#1406=CYLINDRICAL_SURFACE('',#1405,4.);
#1407=ORIENTED_EDGE('',*,*,#285,.T.);
#1408=DIRECTION('',(0.,1.,0.));
#1409=VECTOR('',#1408,1.);
#1410=CARTESIAN_POINT('',(-49.,-1.,30.));
#1411=LINE('',#1410,#1409);
#1412=CARTESIAN_POINT('',(-49.,-1.,30.));
#1413=VERTEX_POINT('',#1412);
#1414=EDGE_CURVE('E326',#1413,#275,#1411,.T.);
#1415=ORIENTED_EDGE('',*,*,#1414,.F.);
#1416=CARTESIAN_POINT('',(-45.,-1.,30.));
#1417=DIRECTION('',(0.,-1.,0.));
#1418=DIRECTION('',(1.,0.,0.));
#1419=AXIS2_PLACEMENT_3D('',#1416,#1417,#1418);
#1420=CIRCLE('',#1419,4.);
#1421=EDGE_CURVE('E295',#1389,#1413,#1420,.T.);
#1422=ORIENTED_EDGE('',*,*,#1421,.F.);
#1423=ORIENTED_EDGE('',*,*,#1390,.T.);
#1424=EDGE_LOOP('',(#1407,#1415,#1422,#1423));
#1425=FACE_BOUND('',#1424,.T.);
#1426=ADVANCED_FACE('F753',(#1425),#1406,.T.);
#1427=CARTESIAN_POINT('',(-49.,-1.,-30.));
#1428=DIRECTION('',(1.,0.,0.));
#1429=DIRECTION('',(0.,0.,-1.));
#1430=AXIS2_PLACEMENT_3D('',#1427,#1428,#1429);
#1431=PLANE('',#1430);
#1432=ORIENTED_EDGE('',*,*,#276,.T.);
#1433=DIRECTION('',(0.,1.,0.));
#1434=VECTOR('',#1433,1.);
#1435=CARTESIAN_POINT('',(-49.,-1.,-30.));
#1436=LINE('',#1435,#1434);
#1437=CARTESIAN_POINT('',(-49.,-1.,-30.));
#1438=VERTEX_POINT('',#1437);
#1439=EDGE_CURVE('E323',#1438,#267,#1436,.T.);
#1440=ORIENTED_EDGE('',*,*,#1439,.F.);
#1441=DIRECTION('',(0.,0.,1.));
#1442=VECTOR('',#1441,1.);
#1443=CARTESIAN_POINT('',(-49.,-1.,-30.));
#1444=LINE('',#1443,#1442);
#1445=EDGE_CURVE('E297',#1413,#1438,#1444,.F.);
#1446=ORIENTED_EDGE('',*,*,#1445,.F.);
#1447=ORIENTED_EDGE('',*,*,#1414,.T.);
#1448=EDGE_LOOP('',(#1432,#1440,#1446,#1447));
#1449=FACE_BOUND('',#1448,.T.);
#1450=ADVANCED_FACE('F759',(#1449),#1431,.F.);
#1451=CARTESIAN_POINT('',(-45.,-1.,-30.));
#1452=DIRECTION('',(0.,1.,0.));
#1453=DIRECTION('',(0.,0.,1.));
#1454=AXIS2_PLACEMENT_3D('',#1451,#1452,#1453);
#1455=CYLINDRICAL_SURFACE('',#1454,4.00000000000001);
#1456=ORIENTED_EDGE('',*,*,#268,.T.);
#1457=DIRECTION('',(0.,1.,0.));
#1458=VECTOR('',#1457,1.);
#1459=CARTESIAN_POINT('',(-45.,-1.,-34.));
#1460=LINE('',#1459,#1458);
#1461=CARTESIAN_POINT('',(-45.,-1.,-34.));
#1462=VERTEX_POINT('',#1461);
#1463=EDGE_CURVE('E320',#1462,#258,#1460,.T.);
#1464=ORIENTED_EDGE('',*,*,#1463,.F.);
#1465=CARTESIAN_POINT('',(-45.,-1.,-30.));
#1466=DIRECTION('',(0.,-1.,0.));
#1467=DIRECTION('',(1.,0.,0.));
#1468=AXIS2_PLACEMENT_3D('',#1465,#1466,#1467);
#1469=CIRCLE('',#1468,4.00000000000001);
#1470=EDGE_CURVE('E299',#1438,#1462,#1469,.T.);
#1471=ORIENTED_EDGE('',*,*,#1470,.F.);
#1472=ORIENTED_EDGE('',*,*,#1439,.T.);
#1473=EDGE_LOOP('',(#1456,#1464,#1471,#1472));
#1474=FACE_BOUND('',#1473,.T.);
#1475=ADVANCED_FACE('F761',(#1474),#1455,.T.);
#1476=CARTESIAN_POINT('',(45.,-1.,-34.));
#1477=DIRECTION('',(0.,0.,1.));
#1478=DIRECTION('',(1.,0.,0.));
#1479=AXIS2_PLACEMENT_3D('',#1476,#1477,#1478);
#1480=PLANE('',#1479);
#1481=ORIENTED_EDGE('',*,*,#259,.T.);
#1482=ORIENTED_EDGE('',*,*,#1348,.F.);
#1483=DIRECTION('',(1.,0.,0.));
#1484=VECTOR('',#1483,1.);
#1485=CARTESIAN_POINT('',(45.,-1.,-34.));
#1486=LINE('',#1485,#1484);
#1487=EDGE_CURVE('E251',#1462,#1341,#1486,.T.);
#1488=ORIENTED_EDGE('',*,*,#1487,.F.);
#1489=ORIENTED_EDGE('',*,*,#1463,.T.);
#1490=EDGE_LOOP('',(#1481,#1482,#1488,#1489));
#1491=FACE_BOUND('',#1490,.T.);
#1492=ADVANCED_FACE('F763',(#1491),#1480,.F.);
#1493=CARTESIAN_POINT('',(45.,-1.,-30.));
#1494=DIRECTION('',(0.,-1.,0.));
#1495=DIRECTION('',(1.,0.,0.));
#1496=AXIS2_PLACEMENT_3D('',#1493,#1494,#1495);
#1497=PLANE('',#1496);
#1498=ORIENTED_EDGE('',*,*,#1342,.T.);
#1499=ORIENTED_EDGE('',*,*,#707,.F.);
#1500=ORIENTED_EDGE('',*,*,#1042,.F.);
#1501=ORIENTED_EDGE('',*,*,#766,.F.);
#1502=ORIENTED_EDGE('',*,*,#963,.F.);
#1503=ORIENTED_EDGE('',*,*,#806,.F.);
#1504=ORIENTED_EDGE('',*,*,#1138,.F.);
#1505=ORIENTED_EDGE('',*,*,#864,.F.);
#1506=ORIENTED_EDGE('',*,*,#1059,.F.);
#1507=ORIENTED_EDGE('',*,*,#674,.F.);
#1508=ORIENTED_EDGE('',*,*,#1372,.T.);
#1509=ORIENTED_EDGE('',*,*,#1396,.T.);
#1510=ORIENTED_EDGE('',*,*,#1421,.T.);
#1511=ORIENTED_EDGE('',*,*,#1445,.T.);
#1512=ORIENTED_EDGE('',*,*,#1470,.T.);
#1513=ORIENTED_EDGE('',*,*,#1487,.T.);
#1514=EDGE_LOOP('',(#1498,#1499,#1500,#1501,#1502,#1503,#1504,#1505,#1506,#1507,#1508,#1509,
#1510,#1511,#1512,#1513));
#1515=FACE_BOUND('',#1514,.T.);
#1516=ADVANCED_FACE('F245',(#1515),#1497,.T.);
#1517=CLOSED_SHELL('',(#76,#116,#174,#236,#353,#377,#395,#413,#431,#457,#474,#499,#523,#541,
#559,#571,#603,#627,#652,#685,#718,#776,#816,#874,#927,#951,#975,#993,#1011,#1029,#1047,#1071,
#1089,#1107,#1125,#1143,#1171,#1191,#1219,#1239,#1259,#1271,#1291,#1303,#1315,#1327,#1352,#1377,
#1401,#1426,#1450,#1475,#1492,#1516));
#1518=MANIFOLD_SOLID_BREP('B2',#1517);
#1519=ADVANCED_BREP_SHAPE_REPRESENTATION('',(#18,#1518),#14);
#1520=SHAPE_DEFINITION_REPRESENTATION(#9,#1519);
ENDSEC;
END-ISO-10303-21;
